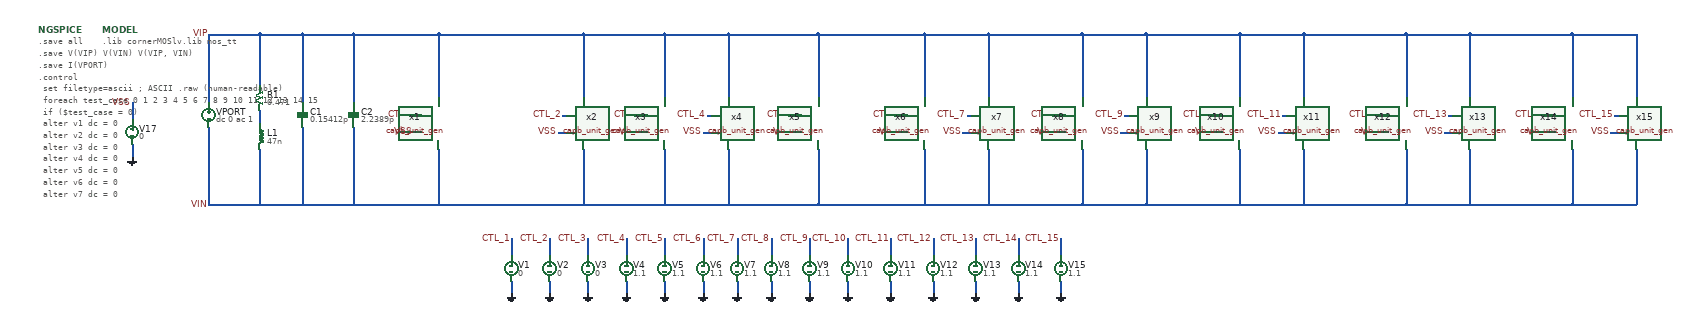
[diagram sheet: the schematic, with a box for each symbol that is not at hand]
v {xschem version=3.4.6 file_version=1.2}
G {}
K {}
V {}
S {}
E {}
N -160 40 -60 40 {lab=VIN}
N 60 -140 60 40 {lab=VIN}
N 60 -360 60 -200 {lab=VIP}
N -280 -360 -280 -200 {lab=VIP}
N -280 -140 -280 40 {lab=VIN}
N 190 -170 220 -170 {lab=CTL_1}
N 550 -170 560 -170 {lab=CTL_2}
N 260 -360 260 -210 {lab=VIP}
N 600 -360 600 -210 {lab=VIP}
N -160 -360 -60 -360 {lab=VIP}
N 720 -170 750 -170 {lab=CTL_3}
N 890 -170 900 -170 {lab=CTL_4}
N 790 -360 790 -210 {lab=VIP}
N 940 -360 940 -210 {lab=VIP}
N 1080 -170 1110 -170 {lab=CTL_5}
N 1330 -170 1360 -170 {lab=CTL_6}
N 1500 -170 1510 -170 {lab=CTL_7}
N 1700 -170 1730 -170 {lab=CTL_8}
N 1870 -170 1880 -170 {lab=CTL_9}
N 2070 -170 2100 -170 {lab=CTL_10}
N 2240 -170 2250 -170 {lab=CTL_11}
N 2290 -360 2290 -210 {lab=VIP}
N 2460 -170 2490 -170 {lab=CTL_12}
N 2630 -170 2640 -170 {lab=CTL_13}
N 2530 -360 2530 -210 {lab=VIP}
N 2680 -360 2680 -210 {lab=VIP}
N 2850 -170 2880 -170 {lab=CTL_14}
N 3020 -170 3030 -170 {lab=CTL_15}
N 2920 -360 2920 -210 {lab=VIP}
N 3070 -360 3070 -210 {lab=VIP}
N 2920 -360 3070 -360 {lab=VIP}
N 600 -360 790 -360 {lab=VIP}
N 790 -360 940 -360 {lab=VIP}
N 2290 -360 2530 -360 {lab=VIP}
N 2530 -360 2680 -360 {lab=VIP}
N 2680 -360 2920 -360 {lab=VIP}
N 2920 40 3070 40 {lab=VIN}
N 600 40 790 40 {lab=VIN}
N 790 40 940 40 {lab=VIN}
N 2140 40 2290 40 {lab=VIN}
N 2290 40 2530 40 {lab=VIN}
N 2530 40 2680 40 {lab=VIN}
N 2680 40 2920 40 {lab=VIN}
N 1920 40 2140 40 {lab=VIN}
N 940 40 1150 40 {lab=VIN}
N 1150 40 1400 40 {lab=VIN}
N 1400 40 1550 40 {lab=VIN}
N 1550 40 1770 40 {lab=VIN}
N 1770 40 1920 40 {lab=VIN}
N 2140 -360 2290 -360 {lab=VIP}
N 2140 -360 2140 -210 {lab=VIP}
N 1920 -360 2140 -360 {lab=VIP}
N 1920 -360 1920 -210 {lab=VIP}
N 1770 -360 1920 -360 {lab=VIP}
N 1770 -360 1770 -210 {lab=VIP}
N 1550 -360 1770 -360 {lab=VIP}
N 1550 -360 1550 -210 {lab=VIP}
N 1400 -360 1550 -360 {lab=VIP}
N 1400 -360 1400 -210 {lab=VIP}
N 1150 -360 1400 -360 {lab=VIP}
N 1150 -360 1150 -210 {lab=VIP}
N 940 -360 1150 -360 {lab=VIP}
N 430 120 430 160 {lab=CTL_1}
N 430 220 430 250 {lab=GND}
N 520 120 520 160 {lab=CTL_2}
N 520 220 520 250 {lab=GND}
N 610 120 610 160 {lab=CTL_3}
N 610 220 610 250 {lab=GND}
N 700 120 700 160 {lab=CTL_4}
N 700 220 700 250 {lab=GND}
N 790 120 790 160 {lab=CTL_5}
N 790 220 790 250 {lab=GND}
N 880 120 880 160 {lab=CTL_6}
N 880 220 880 250 {lab=GND}
N 960 120 960 160 {lab=CTL_7}
N 960 220 960 250 {lab=GND}
N 1040 120 1040 160 {lab=CTL_8}
N 1040 220 1040 250 {lab=GND}
N 1130 120 1130 160 {lab=CTL_9}
N 1130 220 1130 250 {lab=GND}
N 1220 120 1220 160 {lab=CTL_10}
N 1220 220 1220 250 {lab=GND}
N 1320 120 1320 160 {lab=CTL_11}
N 1320 220 1320 250 {lab=GND}
N 1420 120 1420 160 {lab=CTL_12}
N 1420 220 1420 250 {lab=GND}
N 1520 120 1520 160 {lab=CTL_13}
N 1520 220 1520 250 {lab=GND}
N 1620 120 1620 160 {lab=CTL_14}
N 1620 220 1620 250 {lab=GND}
N 1720 120 1720 160 {lab=CTL_15}
N 1720 220 1720 250 {lab=GND}
N 200 -130 220 -130 {lab=VSS}
N -460 -200 -460 -160 {lab=VSS}
N -460 -100 -460 -70 {lab=GND}
N 540 -130 560 -130 {lab=VSS}
N 730 -130 750 -130 {lab=VSS}
N 880 -130 900 -130 {lab=VSS}
N 1090 -130 1110 -130 {lab=VSS}
N 1340 -130 1360 -130 {lab=VSS}
N 1490 -130 1510 -130 {lab=VSS}
N 1710 -130 1730 -130 {lab=VSS}
N 1860 -130 1880 -130 {lab=VSS}
N 2080 -130 2100 -130 {lab=VSS}
N 2230 -130 2250 -130 {lab=VSS}
N 2470 -130 2490 -130 {lab=VSS}
N 2620 -130 2640 -130 {lab=VSS}
N 2860 -130 2880 -130 {lab=VSS}
N 3010 -130 3030 -130 {lab=VSS}
N 260 -90 260 40 {lab=VIN}
N 600 -90 600 40 {lab=VIN}
N 790 -90 790 40 {lab=VIN}
N 940 -90 940 40 {lab=VIN}
N 1150 -90 1150 40 {lab=VIN}
N 1400 -90 1400 40 {lab=VIN}
N 1550 -90 1550 40 {lab=VIN}
N 1770 -90 1770 40 {lab=VIN}
N 1920 -90 1920 40 {lab=VIN}
N 2140 -90 2140 40 {lab=VIN}
N 2290 -90 2290 40 {lab=VIN}
N 2530 -90 2530 40 {lab=VIN}
N 2680 -90 2680 40 {lab=VIN}
N 2920 -90 2920 40 {lab=VIN}
N 3070 -90 3070 40 {lab=VIN}
N -160 -90 -160 40 {lab=VIN}
N -160 -180 -160 -150 {lab=#net1}
N -160 -360 -160 -240 {lab=VIP}
N -60 -360 -60 -200 {lab=VIP}
N -60 -140 -60 40 {lab=VIN}
N 260 40 600 40 {lab=VIN}
N 260 -360 600 -360 {lab=VIP}
N -60 40 60 40 {lab=VIN}
N -60 -360 60 -360 {lab=VIP}
N -280 40 -160 40 {lab=VIN}
N -280 -360 -160 -360 {lab=VIP}
N 60 40 260 40 {lab=VIN}
N 60 -360 260 -360 {lab=VIP}
C {capa.sym} 60 -170 0 0 {name=C2
m=1
value=2.2389p
footprint=1206
device="ceramic capacitor"}
C {lab_pin.sym} 210 -170 0 0 {name=p1 sig_type=std_logic lab=CTL_1}
C {lab_pin.sym} 550 -170 0 0 {name=p2 sig_type=std_logic lab=CTL_2}
C {code.sym} -680 -370 0 0 {name=NGSPICE only_toplevel=true value="

.save all
.save V(VIP) V(VIN) V(VIP, VIN)
.save I(VPORT)


.control
  set filetype=ascii        ; ASCII .raw (human-readable)

  foreach test_case 0 1 2 3 4 5 6 7 8 9 10 11 12 13 14 15
    if ($test_case = 0)
      alter v1 dc = 0
      alter v2 dc = 0
      alter v3 dc = 0
      alter v4 dc = 0
      alter v5 dc = 0
      alter v6 dc = 0
      alter v7 dc = 0
      alter v8 dc = 0
      alter v9 dc = 0
      alter v10 dc = 0
      alter v11 dc = 0
      alter v12 dc = 0
      alter v13 dc = 0
      alter v14 dc = 0
      alter v15 dc = 0
      alter v16 dc = 0
    else
      if ($test_case = 1)
      alter v1 dc = 1.2
      alter v2 dc = 0
      alter v3 dc = 0
      alter v4 dc = 0
      alter v5 dc = 0
      alter v6 dc = 0
      alter v7 dc = 0
      alter v8 dc = 0
      alter v9 dc = 0
      alter v10 dc = 0
      alter v11 dc = 0
      alter v12 dc = 0
      alter v13 dc = 0
      alter v14 dc = 0
      alter v15 dc = 0
      alter v16 dc = 0
      else
      if ($test_case = 2)
      alter v1 dc = 1.2
      alter v2 dc = 1.2
      alter v3 dc = 0
      alter v4 dc = 0
      alter v5 dc = 0
      alter v6 dc = 0
      alter v7 dc = 0
      alter v8 dc = 0
      alter v9 dc = 0
      alter v10 dc = 0
      alter v11 dc = 0
      alter v12 dc = 0
      alter v13 dc = 0
      alter v14 dc = 0
      alter v15 dc = 0
      alter v16 dc = 0
      else
      if ($test_case = 3)
      alter v1 dc = 1.2
      alter v2 dc = 1.2
      alter v3 dc = 1.2
      alter v4 dc = 0
      alter v5 dc = 0
      alter v6 dc = 0
      alter v7 dc = 0
      alter v8 dc = 0
      alter v9 dc = 0
      alter v10 dc = 0
      alter v11 dc = 0
      alter v12 dc = 0
      alter v13 dc = 0
      alter v14 dc = 0
      alter v15 dc = 0
      alter v16 dc = 0
      else
      if ($test_case = 4)
      alter v1 dc = 1.2
      alter v2 dc = 1.2
      alter v3 dc = 1.2
      alter v4 dc = 1.2
      alter v5 dc = 0
      alter v6 dc = 0
      alter v7 dc = 0
      alter v8 dc = 0
      alter v9 dc = 0
      alter v10 dc = 0
      alter v11 dc = 0
      alter v12 dc = 0
      alter v13 dc = 0
      alter v14 dc = 0
      alter v15 dc = 0
      alter v16 dc = 0
      else
      if ($test_case = 5)
      alter v1 dc = 1.2
      alter v2 dc = 1.2
      alter v3 dc = 1.2
      alter v4 dc = 1.2
      alter v5 dc = 1.2
      alter v6 dc = 0
      alter v7 dc = 0
      alter v8 dc = 0
      alter v9 dc = 0
      alter v10 dc = 0
      alter v11 dc = 0
      alter v12 dc = 0
      alter v13 dc = 0
      alter v14 dc = 0
      alter v15 dc = 0
      alter v16 dc = 0
      else
      if ($test_case = 6)
      alter v1 dc = 1.2
      alter v2 dc = 1.2
      alter v3 dc = 1.2
      alter v4 dc = 1.2
      alter v5 dc = 1.2
      alter v6 dc = 1.2
      alter v7 dc = 0
      alter v8 dc = 0
      alter v9 dc = 0
      alter v10 dc = 0
      alter v11 dc = 0
      alter v12 dc = 0
      alter v13 dc = 0
      alter v14 dc = 0
      alter v15 dc = 0
      alter v16 dc = 0
      else
      if ($test_case = 7)
      alter v1 dc = 1.2
      alter v2 dc = 1.2
      alter v3 dc = 1.2
      alter v4 dc = 1.2
      alter v5 dc = 1.2
      alter v6 dc = 1.2
      alter v7 dc = 1.2
      alter v8 dc = 0
      alter v9 dc = 0
      alter v10 dc = 0
      alter v11 dc = 0
      alter v12 dc = 0
      alter v13 dc = 0
      alter v14 dc = 0
      alter v15 dc = 0
      alter v16 dc = 0
      else
      if ($test_case = 8)
      alter v1 dc = 1.2
      alter v2 dc = 1.2
      alter v3 dc = 1.2
      alter v4 dc = 1.2
      alter v5 dc = 1.2
      alter v6 dc = 1.2
      alter v7 dc = 1.2
      alter v8 dc = 1.2
      alter v9 dc = 0
      alter v10 dc = 0
      alter v11 dc = 0
      alter v12 dc = 0
      alter v13 dc = 0
      alter v14 dc = 0
      alter v15 dc = 0
      alter v16 dc = 0
      else
      if ($test_case = 9)
      alter v1 dc = 1.2
      alter v2 dc = 1.2
      alter v3 dc = 1.2
      alter v4 dc = 1.2
      alter v5 dc = 1.2
      alter v6 dc = 1.2
      alter v7 dc = 1.2
      alter v8 dc = 1.2
      alter v9 dc = 1.2
      alter v10 dc = 0
      alter v11 dc = 0
      alter v12 dc = 0
      alter v13 dc = 0
      alter v14 dc = 0
      alter v15 dc = 0
      alter v16 dc = 0
      else
      if ($test_case = 10)
      alter v1 dc = 1.2
      alter v2 dc = 1.2
      alter v3 dc = 1.2
      alter v4 dc = 1.2
      alter v5 dc = 1.2
      alter v6 dc = 1.2
      alter v7 dc = 1.2
      alter v8 dc = 1.2
      alter v9 dc = 1.2
      alter v10 dc = 1.2
      alter v11 dc = 0
      alter v12 dc = 0
      alter v13 dc = 0
      alter v14 dc = 0
      alter v15 dc = 0
      alter v16 dc = 0
      else
      if ($test_case = 11)
      alter v1 dc = 1.2
      alter v2 dc = 1.2
      alter v3 dc = 1.2
      alter v4 dc = 1.2
      alter v5 dc = 1.2
      alter v6 dc = 1.2
      alter v7 dc = 1.2
      alter v8 dc = 1.2
      alter v9 dc = 1.2
      alter v10 dc = 1.2
      alter v11 dc = 1.2
      alter v12 dc = 0
      alter v13 dc = 0
      alter v14 dc = 0
      alter v15 dc = 0
      alter v16 dc = 0
      else
      if ($test_case = 12)
      alter v1 dc = 1.2
      alter v2 dc = 1.2
      alter v3 dc = 1.2
      alter v4 dc = 1.2
      alter v5 dc = 1.2
      alter v6 dc = 1.2
      alter v7 dc = 1.2
      alter v8 dc = 1.2
      alter v9 dc = 1.2
      alter v10 dc = 1.2
      alter v11 dc = 1.2
      alter v12 dc = 1.2
      alter v13 dc = 0
      alter v14 dc = 0
      alter v15 dc = 0
      alter v16 dc = 0
      else
      if ($test_case = 13)
      alter v1 dc = 1.2
      alter v2 dc = 1.2
      alter v3 dc = 1.2
      alter v4 dc = 1.2
      alter v5 dc = 1.2
      alter v6 dc = 1.2
      alter v7 dc = 1.2
      alter v8 dc = 1.2
      alter v9 dc = 1.2
      alter v10 dc = 1.2
      alter v11 dc = 1.2
      alter v12 dc = 1.2
      alter v13 dc = 1.2
      alter v14 dc = 0
      alter v15 dc = 0
      alter v16 dc = 0
      else
      if ($test_case = 14)
      alter v1 dc = 1.2
      alter v2 dc = 1.2
      alter v3 dc = 1.2
      alter v4 dc = 1.2
      alter v5 dc = 1.2
      alter v6 dc = 1.2
      alter v7 dc = 1.2
      alter v8 dc = 1.2
      alter v9 dc = 1.2
      alter v10 dc = 1.2
      alter v11 dc = 1.2
      alter v12 dc = 1.2
      alter v13 dc = 1.2
      alter v14 dc = 1.2
      alter v15 dc = 0
      alter v16 dc = 0
      else
      if ($test_case = 15)
      alter v1 dc = 1.2
      alter v2 dc = 1.2
      alter v3 dc = 1.2
      alter v4 dc = 1.2
      alter v5 dc = 1.2
      alter v6 dc = 1.2
      alter v7 dc = 1.2
      alter v8 dc = 1.2
      alter v9 dc = 1.2
      alter v10 dc = 1.2
      alter v11 dc = 1.2
      alter v12 dc = 1.2
      alter v13 dc = 1.2
      alter v14 dc = 1.2
      alter v15 dc = 1.2
      alter v16 dc = 0
      else
      alter v1 dc = 1.2
      alter v2 dc = 1.2
      alter v3 dc = 1.2
      alter v4 dc = 1.2
      alter v5 dc = 1.2
      alter v6 dc = 1.2
      alter v7 dc = 1.2
      alter v8 dc = 1.2
      alter v9 dc = 1.2
      alter v10 dc = 1.2
      alter v11 dc = 1.2
      alter v12 dc = 1.2
      alter v13 dc = 1.2
      alter v14 dc = 1.2
      alter v15 dc = 1.2
      alter v16 dc = 1.2
      end
      end
      end
      end
      end
      end
      end
      end
      end
      end
      end
      end
      end
      end
      end
    end

    run
    ac lin 5000 300Meg 600Meg
    *tran 0.1u 100u
    let ZIN  = v(VIP, VIN)/i(VPORT)
    let ABSZ = abs(ZIN)
    let IMZ  = imag(ZIN)
    let REZ  = real(ZIN)
    meas ac F_res when IMZ=0
    write tb_capb_g1.raw ABSZ
    set appendwrite
  end
.endc
"}
C {code.sym} -530 -370 0 0 {name=MODEL only_toplevel=true
format="tcleval( @value )"
value="
.lib cornerMOSlv.lib mos_tt
"}
C {vsource.sym} -280 -170 0 0 {name=VPORT value="dc 0 ac 1" savecurrent=false}
C {lab_pin.sym} -280 -360 0 0 {name=p33 sig_type=std_logic lab=VIP}
C {lab_pin.sym} -280 40 0 0 {name=p52 sig_type=std_logic lab=VIN}
C {lab_pin.sym} 740 -170 0 0 {name=p3 sig_type=std_logic lab=CTL_3}
C {lab_pin.sym} 890 -170 0 0 {name=p4 sig_type=std_logic lab=CTL_4}
C {lab_pin.sym} 1100 -170 0 0 {name=p5 sig_type=std_logic lab=CTL_5}
C {lab_pin.sym} 1350 -170 0 0 {name=p7 sig_type=std_logic lab=CTL_6}
C {lab_pin.sym} 1500 -170 0 0 {name=p8 sig_type=std_logic lab=CTL_7}
C {lab_pin.sym} 1720 -170 0 0 {name=p9 sig_type=std_logic lab=CTL_8
}
C {lab_pin.sym} 1870 -170 0 0 {name=p10 sig_type=std_logic lab=CTL_9}
C {lab_pin.sym} 2090 -170 0 0 {name=p11 sig_type=std_logic lab=CTL_10}
C {lab_pin.sym} 2240 -170 0 0 {name=p12 sig_type=std_logic lab=CTL_11}
C {lab_pin.sym} 2480 -170 0 0 {name=p13 sig_type=std_logic lab=CTL_12}
C {lab_pin.sym} 2630 -170 0 0 {name=p14 sig_type=std_logic lab=CTL_13}
C {lab_pin.sym} 2870 -170 0 0 {name=p15 sig_type=std_logic lab=CTL_14}
C {lab_pin.sym} 3020 -170 0 0 {name=p16 sig_type=std_logic lab=CTL_15}
C {vsource.sym} 430 190 0 0 {name=V1 value=0 savecurrent=false}
C {lab_pin.sym} 430 120 0 0 {name=p17 sig_type=std_logic lab=CTL_1}
C {gnd.sym} 430 250 0 0 {name=l2 lab=GND}
C {vsource.sym} 520 190 0 0 {name=V2 value=0 savecurrent=false}
C {lab_pin.sym} 520 120 0 0 {name=p18 sig_type=std_logic lab=CTL_2}
C {gnd.sym} 520 250 0 0 {name=l3 lab=GND}
C {vsource.sym} 610 190 0 0 {name=V3 value=0 savecurrent=false}
C {lab_pin.sym} 610 120 0 0 {name=p19 sig_type=std_logic lab=CTL_3}
C {gnd.sym} 610 250 0 0 {name=l7 lab=GND}
C {vsource.sym} 700 190 0 0 {name=V4 value=1.1 savecurrent=false}
C {lab_pin.sym} 700 120 0 0 {name=p20 sig_type=std_logic lab=CTL_4}
C {gnd.sym} 700 250 0 0 {name=l20 lab=GND}
C {vsource.sym} 790 190 0 0 {name=V5 value=1.1 savecurrent=false}
C {lab_pin.sym} 790 120 0 0 {name=p21 sig_type=std_logic lab=CTL_5}
C {gnd.sym} 790 250 0 0 {name=l21 lab=GND}
C {vsource.sym} 880 190 0 0 {name=V6 value=1.1 savecurrent=false}
C {lab_pin.sym} 880 120 0 0 {name=p22 sig_type=std_logic lab=CTL_6}
C {gnd.sym} 880 250 0 0 {name=l22 lab=GND}
C {vsource.sym} 960 190 0 0 {name=V7 value=1.1 savecurrent=false}
C {lab_pin.sym} 960 120 0 0 {name=p23 sig_type=std_logic lab=CTL_7}
C {gnd.sym} 960 250 0 0 {name=l23 lab=GND}
C {vsource.sym} 1040 190 0 0 {name=V8 value=1.1 savecurrent=false}
C {lab_pin.sym} 1040 120 0 0 {name=p24 sig_type=std_logic lab=CTL_8}
C {gnd.sym} 1040 250 0 0 {name=l24 lab=GND}
C {vsource.sym} 1130 190 0 0 {name=V9 value=1.1 savecurrent=false}
C {lab_pin.sym} 1130 120 0 0 {name=p25 sig_type=std_logic lab=CTL_9}
C {gnd.sym} 1130 250 0 0 {name=l25 lab=GND}
C {vsource.sym} 1220 190 0 0 {name=V10 value=1.1 savecurrent=false}
C {lab_pin.sym} 1220 120 0 0 {name=p26 sig_type=std_logic lab=CTL_10}
C {gnd.sym} 1220 250 0 0 {name=l26 lab=GND}
C {vsource.sym} 1320 190 0 0 {name=V11 value=1.1 savecurrent=false}
C {lab_pin.sym} 1320 120 0 0 {name=p27 sig_type=std_logic lab=CTL_11}
C {gnd.sym} 1320 250 0 0 {name=l27 lab=GND}
C {vsource.sym} 1420 190 0 0 {name=V12 value=1.1 savecurrent=false}
C {lab_pin.sym} 1420 120 0 0 {name=p28 sig_type=std_logic lab=CTL_12}
C {gnd.sym} 1420 250 0 0 {name=l28 lab=GND}
C {vsource.sym} 1520 190 0 0 {name=V13 value=1.1 savecurrent=false}
C {lab_pin.sym} 1520 120 0 0 {name=p29 sig_type=std_logic lab=CTL_13}
C {gnd.sym} 1520 250 0 0 {name=l29 lab=GND}
C {vsource.sym} 1620 190 0 0 {name=V14 value=1.1 savecurrent=false}
C {lab_pin.sym} 1620 120 0 0 {name=p30 sig_type=std_logic lab=CTL_14}
C {gnd.sym} 1620 250 0 0 {name=l30 lab=GND}
C {vsource.sym} 1720 190 0 0 {name=V15 value=1.1 savecurrent=false}
C {lab_pin.sym} 1720 120 0 0 {name=p31 sig_type=std_logic lab=CTL_15}
C {gnd.sym} 1720 250 0 0 {name=l31 lab=GND}
C {capb_unit_gen.sym} 260 -150 0 0 {name=x1
Ls=47e-9
Rs=0.471
f_sr=1870e6
q_coil=289
f_op=433e6
b=4
schematic="capb_unit.py(@Ls\\,@Rs\\,@f_sr\\,@q_coil\\,@f_op\\,@b\\)"
tclcommand="edit_file [abs_sym_path capb_unit.py]"}
C {lab_pin.sym} 200 -130 0 0 {name=p34 sig_type=std_logic lab=VSS}
C {vsource.sym} -460 -130 0 0 {name=V17 value=0 savecurrent=false}
C {lab_pin.sym} -460 -200 0 0 {name=p35 sig_type=std_logic lab=VSS}
C {gnd.sym} -460 -70 0 0 {name=l4 lab=GND}
C {lab_pin.sym} 540 -130 0 0 {name=p36 sig_type=std_logic lab=VSS}
C {lab_pin.sym} 730 -130 0 0 {name=p37 sig_type=std_logic lab=VSS}
C {lab_pin.sym} 880 -130 0 0 {name=p38 sig_type=std_logic lab=VSS}
C {lab_pin.sym} 1090 -130 0 0 {name=p39 sig_type=std_logic lab=VSS}
C {lab_pin.sym} 1340 -130 0 0 {name=p40 sig_type=std_logic lab=VSS}
C {lab_pin.sym} 1490 -130 0 0 {name=p41 sig_type=std_logic lab=VSS}
C {lab_pin.sym} 1710 -130 0 0 {name=p42 sig_type=std_logic lab=VSS}
C {lab_pin.sym} 1860 -130 0 0 {name=p43 sig_type=std_logic lab=VSS}
C {lab_pin.sym} 2080 -130 0 0 {name=p44 sig_type=std_logic lab=VSS}
C {lab_pin.sym} 2230 -130 0 0 {name=p45 sig_type=std_logic lab=VSS}
C {lab_pin.sym} 2470 -130 0 0 {name=p46 sig_type=std_logic lab=VSS}
C {lab_pin.sym} 2620 -130 0 0 {name=p47 sig_type=std_logic lab=VSS}
C {lab_pin.sym} 2860 -130 0 0 {name=p48 sig_type=std_logic lab=VSS}
C {lab_pin.sym} 3010 -130 0 0 {name=p49 sig_type=std_logic lab=VSS}
C {ind.sym} -160 -120 0 0 {name=L1
m=1
value=47n
footprint=1206
device=inductor}
C {res.sym} -160 -210 0 0 {name=R1
value=0.471
footprint=1206
device=resistor
m=1}
C {capa.sym} -60 -170 0 0 {name=C1
m=1
value=0.15412p
footprint=1206
device="ceramic capacitor"}
C {capb_unit_gen.sym} 600 -150 0 0 {name=x2
Ls=47e-9
Rs=0.471
f_sr=1870e6
q_coil=289
f_op=433e6
b=4
schematic="capb_unit.py(@Ls\\,@Rs\\,@f_sr\\,@q_coil\\,@f_op\\,@b\\)"
tclcommand="edit_file [abs_sym_path capb_unit.py]"}
C {capb_unit_gen.sym} 790 -150 0 0 {name=x3
Ls=47e-9
Rs=0.471
f_sr=1870e6
q_coil=289
f_op=433e6
b=4
schematic="capb_unit.py(@Ls\\,@Rs\\,@f_sr\\,@q_coil\\,@f_op\\,@b\\)"
tclcommand="edit_file [abs_sym_path capb_unit.py]"}
C {capb_unit_gen.sym} 940 -150 0 0 {name=x4
Ls=47e-9
Rs=0.471
f_sr=1870e6
q_coil=289
f_op=433e6
b=4
schematic="capb_unit.py(@Ls\\,@Rs\\,@f_sr\\,@q_coil\\,@f_op\\,@b\\)"
tclcommand="edit_file [abs_sym_path capb_unit.py]"}
C {capb_unit_gen.sym} 1150 -150 0 0 {name=x5
Ls=47e-9
Rs=0.471
f_sr=1870e6
q_coil=289
f_op=433e6
b=4
schematic="capb_unit.py(@Ls\\,@Rs\\,@f_sr\\,@q_coil\\,@f_op\\,@b\\)"
tclcommand="edit_file [abs_sym_path capb_unit.py]"}
C {capb_unit_gen.sym} 1400 -150 0 0 {name=x6
Ls=47e-9
Rs=0.471
f_sr=1870e6
q_coil=289
f_op=433e6
b=4
schematic="capb_unit.py(@Ls\\,@Rs\\,@f_sr\\,@q_coil\\,@f_op\\,@b\\)"
tclcommand="edit_file [abs_sym_path capb_unit.py]"}
C {capb_unit_gen.sym} 1550 -150 0 0 {name=x7
Ls=47e-9
Rs=0.471
f_sr=1870e6
q_coil=289
f_op=433e6
b=4
schematic="capb_unit.py(@Ls\\,@Rs\\,@f_sr\\,@q_coil\\,@f_op\\,@b\\)"
tclcommand="edit_file [abs_sym_path capb_unit.py]"}
C {capb_unit_gen.sym} 1770 -150 0 0 {name=x8
Ls=47e-9
Rs=0.471
f_sr=1870e6
q_coil=289
f_op=433e6
b=4
schematic="capb_unit.py(@Ls\\,@Rs\\,@f_sr\\,@q_coil\\,@f_op\\,@b\\)"
tclcommand="edit_file [abs_sym_path capb_unit.py]"}
C {capb_unit_gen.sym} 1920 -150 0 0 {name=x9
Ls=47e-9
Rs=0.471
f_sr=1870e6
q_coil=289
f_op=433e6
b=4
schematic="capb_unit.py(@Ls\\,@Rs\\,@f_sr\\,@q_coil\\,@f_op\\,@b\\)"
tclcommand="edit_file [abs_sym_path capb_unit.py]"}
C {capb_unit_gen.sym} 2140 -150 0 0 {name=x10
Ls=47e-9
Rs=0.471
f_sr=1870e6
q_coil=289
f_op=433e6
b=4
schematic="capb_unit.py(@Ls\\,@Rs\\,@f_sr\\,@q_coil\\,@f_op\\,@b\\)"
tclcommand="edit_file [abs_sym_path capb_unit.py]"}
C {capb_unit_gen.sym} 2290 -150 0 0 {name=x11
Ls=47e-9
Rs=0.471
f_sr=1870e6
q_coil=289
f_op=433e6
b=4
schematic="capb_unit.py(@Ls\\,@Rs\\,@f_sr\\,@q_coil\\,@f_op\\,@b\\)"
tclcommand="edit_file [abs_sym_path capb_unit.py]"}
C {capb_unit_gen.sym} 2530 -150 0 0 {name=x12
Ls=47e-9
Rs=0.471
f_sr=1870e6
q_coil=289
f_op=433e6
b=4
schematic="capb_unit.py(@Ls\\,@Rs\\,@f_sr\\,@q_coil\\,@f_op\\,@b\\)"
tclcommand="edit_file [abs_sym_path capb_unit.py]"}
C {capb_unit_gen.sym} 2680 -150 0 0 {name=x13
Ls=47e-9
Rs=0.471
f_sr=1870e6
q_coil=289
f_op=433e6
b=4
schematic="capb_unit.py(@Ls\\,@Rs\\,@f_sr\\,@q_coil\\,@f_op\\,@b\\)"
tclcommand="edit_file [abs_sym_path capb_unit.py]"}
C {capb_unit_gen.sym} 2920 -150 0 0 {name=x14
Ls=47e-9
Rs=0.471
f_sr=1870e6
q_coil=289
f_op=433e6
b=4
schematic="capb_unit.py(@Ls\\,@Rs\\,@f_sr\\,@q_coil\\,@f_op\\,@b\\)"
tclcommand="edit_file [abs_sym_path capb_unit.py]"}
C {capb_unit_gen.sym} 3070 -150 0 0 {name=x15
Ls=47e-9
Rs=0.471
f_sr=1870e6
q_coil=289
f_op=433e6
b=4
schematic="capb_unit.py(@Ls\\,@Rs\\,@f_sr\\,@q_coil\\,@f_op\\,@b\\)"
tclcommand="edit_file [abs_sym_path capb_unit.py]"}
